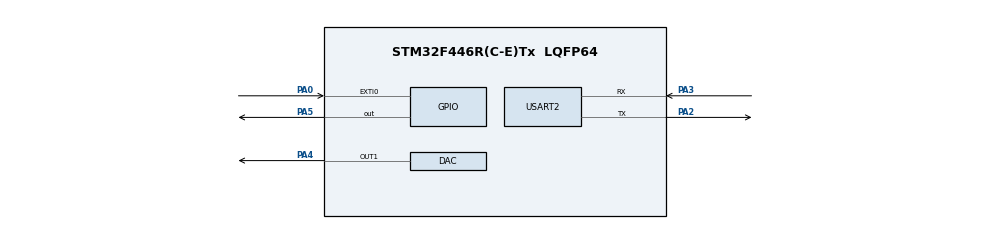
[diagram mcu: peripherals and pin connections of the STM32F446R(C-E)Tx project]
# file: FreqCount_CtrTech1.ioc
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DAC.DAC_Trigger=DAC_TRIGGER_T2_TRGO
Mcu.Family=STM32F4
Mcu.Name=STM32F446R(C-E)Tx
Mcu.Package=LQFP64
NVIC.EXTI0_IRQn=true\:0\:0\:false\:false\:true\:true\:true
NVIC.PriorityGroup=NVIC_PRIORITYGROUP_0
NVIC.TIM3_IRQn=true\:0\:0\:false\:false\:true\:true\:true
NVIC.USART2_IRQn=true\:0\:0\:false\:false\:true\:true\:true
PA0-WKUP.Signal=GPXTI0
PA2.Mode=Asynchronous
PA2.Signal=USART2_TX
PA3.Mode=Asynchronous
PA3.Signal=USART2_RX
PA4.Signal=COMP_DAC1_group
PA5.Signal=GPIO_Output
PH0-OSC_IN.Mode=HSE-External-Oscillator
PH0-OSC_IN.Signal=RCC_OSC_IN
PH1-OSC_OUT.Mode=HSE-External-Oscillator
PH1-OSC_OUT.Signal=RCC_OSC_OUT
ProjectManager.HeapSize=0x200
ProjectManager.StackSize=0x400
ProjectManager.TargetToolchain=STM32CubeIDE
RCC.AHBFreq_Value=90000000
RCC.APB1CLKDivider=RCC_HCLK_DIV4
RCC.APB1Freq_Value=22500000
RCC.APB1TimFreq_Value=45000000
RCC.APB2CLKDivider=RCC_HCLK_DIV4
RCC.APB2Freq_Value=22500000
RCC.APB2TimFreq_Value=45000000
RCC.CortexFreq_Value=90000000
RCC.FLatency-AdvancedSettings=FLASH_LATENCY_2
RCC.HCLKFreq_Value=90000000
RCC.HSE_VALUE=8000000
RCC.HSI_VALUE=16000000
RCC.LSE_VALUE=32768
RCC.PLLM=4
RCC.PLLN=90
RCC.PLLSourceVirtual=RCC_PLLSOURCE_HSE
RCC.SYSCLKFreq_VALUE=90000000
RCC.SYSCLKSource=RCC_SYSCLKSOURCE_PLLCLK
RCC.USBFreq_Value=90000000
RCC.VCOOutputFreq_Value=180000000
SH.COMP_DAC1_group.0=DAC_OUT1,DAC_OUT1
TIM2.Period=0xffffffff
TIM2.Prescaler=45-1
TIM3.Period=0xffff
TIM3.Prescaler=45-1
USART2.VirtualMode=VM_ASYNC
VP_TIM2_VS_ClockSourceINT.Mode=Internal
VP_TIM3_VS_ClockSourceINT.Mode=Internal
board=NUCLEO-F446RE

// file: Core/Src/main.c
/* USER CODE BEGIN Header */
/**
 ******************************************************************************
 * @file           : main.c
 * @brief          : Main program body
 ******************************************************************************
 * @attention
 *
 * <h2><center>&copy; Copyright (c) 2020 STMicroelectronics.
 * All rights reserved.</center></h2>
 *
 * This software component is licensed by ST under BSD 3-Clause license,
 * the "License"; You may not use this file except in compliance with the
 * License. You may obtain a copy of the License at:
 *                        opensource.org/licenses/BSD-3-Clause
 *
 ******************************************************************************
 */
/* USER CODE END Header */

#include "main.h"

/* USER CODE BEGIN Includes */
#include "freqIO.h"
/* USER CODE END Includes */

DAC_HandleTypeDef hdac;

TIM_HandleTypeDef htim2;
TIM_HandleTypeDef htim3;

UART_HandleTypeDef huart2;

void SystemClock_Config(void);
static void MX_GPIO_Init(void);
static void MX_TIM2_Init(void);
static void MX_USART2_UART_Init(void);
static void MX_DAC_Init(void);
static void MX_TIM3_Init(void);

int main(void) {
	/* USER CODE BEGIN 1 */
	//gets a raw memory block,suitable for a Data Type, and sets as memory address
	/* USER CODE END 1 */

	/* MCU Configuration--------------------------------------------------------*/

	/* Reset of all peripherals, Initializes the Flash interface and the Systick. */
	HAL_Init();

	/* Configure the system clock */
	SystemClock_Config();

	/* Initialize all configured peripherals */
	MX_GPIO_Init();
	MX_TIM2_Init();
	MX_USART2_UART_Init();
	MX_DAC_Init();
	MX_TIM3_Init();
	/* USER CODE BEGIN 2 */
	HAL_TIM_Base_Start(&htim2);
	HAL_TIM_Base_Start_IT(&htim3);

	get_sineval();
	edit_sineval(lowFrequency, LOWF);
	edit_sineval(highFrequency, HIGHF);
	bool bitStream[10];

	bitStream[0] = 1;
	bitStream[1] = 1;
	bitStream[2] = 1;
	bitStream[3] = 0;
	bitStream[4] = 0;
	bitStream[5] = 0;
	bitStream[6] = 1;
	bitStream[7] = 0;
	bitStream[8] = 0;
	bitStream[9] = 0;
	HAL_DAC_Start_DMA(&hdac, DAC_CHANNEL_1, highFrequency, HIGHF,
	DAC_ALIGN_12B_R);
	HAL_Delay(500);
	HAL_DAC_Stop_DMA(&hdac, DAC_CHANNEL_1);
	/* USER CODE END 2 */

	/* Infinite loop */
	while (1) {

		/* USER CODE BEGIN 3 */

		for (int i = 0; i < BUFFERSIZE; i++) {
			sprintf(uartData, "Bit value for index %d = %d\r\n", i,
					freqtobit(periodBuffer[i]));
			HAL_UART_Transmit(&huart2, uartData, strlen(uartData), 10);
		}

		//bitToAudio(&bitStream,10);
	}
	/* USER CODE END 3 */
}

void SystemClock_Config(void) {
	RCC_OscInitTypeDef RCC_OscInitStruct = { 0 };
	RCC_ClkInitTypeDef RCC_ClkInitStruct = { 0 };

	/** Configure the main internal regulator output voltage
	 */
	__HAL_RCC_PWR_CLK_ENABLE();
	__HAL_PWR_VOLTAGESCALING_CONFIG(PWR_REGULATOR_VOLTAGE_SCALE3);
	/** Initializes the CPU, AHB and APB busses clocks
	 */
	RCC_OscInitStruct.OscillatorType = RCC_OSCILLATORTYPE_HSE;
	RCC_OscInitStruct.HSEState = RCC_HSE_ON;
	RCC_OscInitStruct.PLL.PLLState = RCC_PLL_ON;
	RCC_OscInitStruct.PLL.PLLSource = RCC_PLLSOURCE_HSE;
	RCC_OscInitStruct.PLL.PLLM = 4;
	RCC_OscInitStruct.PLL.PLLN = 90;
	RCC_OscInitStruct.PLL.PLLP = RCC_PLLP_DIV2;
	RCC_OscInitStruct.PLL.PLLQ = 2;
	RCC_OscInitStruct.PLL.PLLR = 2;
	if (HAL_RCC_OscConfig(&RCC_OscInitStruct) != HAL_OK) {
		Error_Handler();
	}
	/** Initializes the CPU, AHB and APB busses clocks
	 */
	RCC_ClkInitStruct.ClockType = RCC_CLOCKTYPE_HCLK | RCC_CLOCKTYPE_SYSCLK
			| RCC_CLOCKTYPE_PCLK1 | RCC_CLOCKTYPE_PCLK2;
	RCC_ClkInitStruct.SYSCLKSource = RCC_SYSCLKSOURCE_PLLCLK;
	RCC_ClkInitStruct.AHBCLKDivider = RCC_SYSCLK_DIV1;
	RCC_ClkInitStruct.APB1CLKDivider = RCC_HCLK_DIV2;
	RCC_ClkInitStruct.APB2CLKDivider = RCC_HCLK_DIV2;

	if (HAL_RCC_ClockConfig(&RCC_ClkInitStruct, FLASH_LATENCY_2) != HAL_OK) {
		Error_Handler();
	}
}

static void MX_DAC_Init(void) {

	DAC_ChannelConfTypeDef sConfig = { 0 };

	/** DAC Initialization
	 */
	hdac.Instance = DAC;
	if (HAL_DAC_Init(&hdac) != HAL_OK) {
		Error_Handler();
	}
	/** DAC channel OUT1 config
	 */
	sConfig.DAC_Trigger = DAC_TRIGGER_T2_TRGO;
	sConfig.DAC_OutputBuffer = DAC_OUTPUTBUFFER_ENABLE;
	if (HAL_DAC_ConfigChannel(&hdac, &sConfig, DAC_CHANNEL_1) != HAL_OK) {
		Error_Handler();
	}

}

static void MX_TIM2_Init(void) {

	TIM_ClockConfigTypeDef sClockSourceConfig = { 0 };
	TIM_MasterConfigTypeDef sMasterConfig = { 0 };

	htim2.Instance = TIM2;
	htim2.Init.Prescaler = 9 - 1;
	htim2.Init.CounterMode = TIM_COUNTERMODE_UP;
	htim2.Init.Period = 10000 - 1;
	htim2.Init.ClockDivision = TIM_CLOCKDIVISION_DIV1;
	htim2.Init.AutoReloadPreload = TIM_AUTORELOAD_PRELOAD_DISABLE;
	if (HAL_TIM_Base_Init(&htim2) != HAL_OK) {
		Error_Handler();
	}
	sClockSourceConfig.ClockSource = TIM_CLOCKSOURCE_INTERNAL;
	if (HAL_TIM_ConfigClockSource(&htim2, &sClockSourceConfig) != HAL_OK) {
		Error_Handler();
	}
	sMasterConfig.MasterOutputTrigger = TIM_TRGO_RESET;
	sMasterConfig.MasterSlaveMode = TIM_MASTERSLAVEMODE_DISABLE;
	if (HAL_TIMEx_MasterConfigSynchronization(&htim2, &sMasterConfig)
			!= HAL_OK) {
		Error_Handler();
	}

}

static void MX_TIM3_Init(void) {

	TIM_ClockConfigTypeDef sClockSourceConfig = { 0 };
	TIM_MasterConfigTypeDef sMasterConfig = { 0 };

	htim3.Instance = TIM3;
	htim3.Init.Prescaler = 45 - 1;
	htim3.Init.CounterMode = TIM_COUNTERMODE_UP;
	htim3.Init.Period = 0xffff;
	htim3.Init.ClockDivision = TIM_CLOCKDIVISION_DIV1;
	htim3.Init.AutoReloadPreload = TIM_AUTORELOAD_PRELOAD_DISABLE;
	if (HAL_TIM_Base_Init(&htim3) != HAL_OK) {
		Error_Handler();
	}
	sClockSourceConfig.ClockSource = TIM_CLOCKSOURCE_INTERNAL;
	if (HAL_TIM_ConfigClockSource(&htim3, &sClockSourceConfig) != HAL_OK) {
		Error_Handler();
	}
	sMasterConfig.MasterOutputTrigger = TIM_TRGO_RESET;
	sMasterConfig.MasterSlaveMode = TIM_MASTERSLAVEMODE_DISABLE;
	if (HAL_TIMEx_MasterConfigSynchronization(&htim3, &sMasterConfig)
			!= HAL_OK) {
		Error_Handler();
	}

}

static void MX_USART2_UART_Init(void) {

	huart2.Instance = USART2;
	huart2.Init.BaudRate = 115200;
	huart2.Init.WordLength = UART_WORDLENGTH_8B;
	huart2.Init.StopBits = UART_STOPBITS_1;
	huart2.Init.Parity = UART_PARITY_NONE;
	huart2.Init.Mode = UART_MODE_TX_RX;
	huart2.Init.HwFlowCtl = UART_HWCONTROL_NONE;
	huart2.Init.OverSampling = UART_OVERSAMPLING_16;
	if (HAL_UART_Init(&huart2) != HAL_OK) {
		Error_Handler();
	}

}

static void MX_GPIO_Init(void) {
	GPIO_InitTypeDef GPIO_InitStruct = { 0 };

	/* GPIO Ports Clock Enable */
	__HAL_RCC_GPIOH_CLK_ENABLE();
	__HAL_RCC_GPIOA_CLK_ENABLE();

	/*Configure GPIO pin Output Level */
	HAL_GPIO_WritePin(GPIOA, GPIO_PIN_5, GPIO_PIN_RESET);

	/*Configure GPIO pin : PA0 */
	GPIO_InitStruct.Pin = GPIO_PIN_0;
	GPIO_InitStruct.Mode = GPIO_MODE_IT_RISING;
	GPIO_InitStruct.Pull = GPIO_NOPULL;
	HAL_GPIO_Init(GPIOA, &GPIO_InitStruct);

	/*Configure GPIO pin : PA5 */
	GPIO_InitStruct.Pin = GPIO_PIN_5;
	GPIO_InitStruct.Mode = GPIO_MODE_OUTPUT_PP;
	GPIO_InitStruct.Pull = GPIO_NOPULL;
	GPIO_InitStruct.Speed = GPIO_SPEED_FREQ_LOW;
	HAL_GPIO_Init(GPIOA, &GPIO_InitStruct);

	/* EXTI interrupt init*/
	HAL_NVIC_SetPriority(EXTI0_IRQn, 0, 0);
	HAL_NVIC_EnableIRQ(EXTI0_IRQn);

}

/* USER CODE BEGIN 4 */
void HAL_TIM_PeriodElapsedCallback(TIM_HandleTypeDef *htim) {
	if (htim == &htim3)
		Tim3IT();
	else
		__NOP();
}
void HAL_GPIO_EXTI_Callback(uint16_t GPIO_Pin) {
	if (GPIO_Pin == GPIO_PIN_0) {
		FreqCounterPinEXTI();
	} else
		__NOP();
}

/* USER CODE END 4 */

void Error_Handler(void) {
}

/************************ (C) COPYRIGHT STMicroelectronics *****END OF FILE****/
